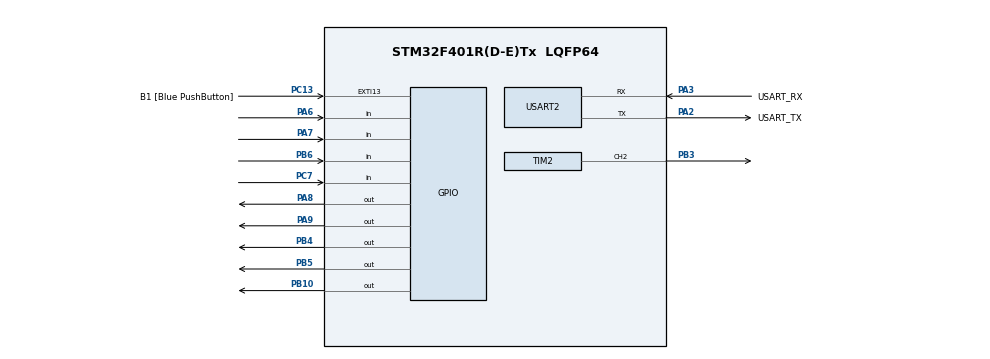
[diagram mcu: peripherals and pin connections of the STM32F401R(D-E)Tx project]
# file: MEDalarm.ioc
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Mcu.Family=STM32F4
Mcu.Name=STM32F401R(D-E)Tx
Mcu.Package=LQFP64
NVIC.PriorityGroup=NVIC_PRIORITYGROUP_0
PA13.GPIO_Label=TMS
PA13.Mode=Serial_Wire
PA13.Signal=SYS_JTMS-SWDIO
PA14.GPIO_Label=TCK
PA14.Mode=Serial_Wire
PA14.Signal=SYS_JTCK-SWCLK
PA2.GPIO_Label=USART_TX
PA2.GPIO_Mode=GPIO_MODE_AF_PP
PA2.GPIO_PuPd=GPIO_NOPULL
PA2.GPIO_Speed=GPIO_SPEED_FREQ_LOW
PA2.Mode=Asynchronous
PA2.Signal=USART2_TX
PA3.GPIO_Label=USART_RX
PA3.GPIO_Mode=GPIO_MODE_AF_PP
PA3.GPIO_PuPd=GPIO_NOPULL
PA3.GPIO_Speed=GPIO_SPEED_FREQ_LOW
PA3.Mode=Asynchronous
PA3.Signal=USART2_RX
PA6.Signal=GPIO_Input
PA7.Signal=GPIO_Input
PA8.Signal=GPIO_Output
PA9.Signal=GPIO_Output
PB10.Signal=GPIO_Output
PB3.Signal=S_TIM2_CH2
PB4.Signal=GPIO_Output
PB5.Signal=GPIO_Output
PB6.Signal=GPIO_Input
PC13-ANTI_TAMP.GPIO_Label=B1 [Blue PushButton]
PC13-ANTI_TAMP.GPIO_ModeDefaultEXTI=GPIO_MODE_IT_FALLING
PC13-ANTI_TAMP.GPIO_PuPd=GPIO_NOPULL
PC13-ANTI_TAMP.Signal=GPXTI13
PC14-OSC32_IN.Mode=LSE-External-Oscillator
PC14-OSC32_IN.Signal=RCC_OSC32_IN
PC15-OSC32_OUT.Mode=LSE-External-Oscillator
PC15-OSC32_OUT.Signal=RCC_OSC32_OUT
PC7.Signal=GPIO_Input
PH0\ -\ OSC_IN.Mode=HSE-External-Clock-Source
PH0\ -\ OSC_IN.Signal=RCC_OSC_IN
PH1\ -\ OSC_OUT.Mode=HSE-External-Clock-Source
PH1\ -\ OSC_OUT.Signal=RCC_OSC_OUT
ProjectManager.HeapSize=0x200
ProjectManager.StackSize=0x400
ProjectManager.TargetToolchain=STM32CubeIDE
RCC.48MHZClocksFreq_Value=48000000
RCC.AHBFreq_Value=84000000
RCC.APB1CLKDivider=RCC_HCLK_DIV2
RCC.APB1Freq_Value=42000000
RCC.APB1TimFreq_Value=84000000
RCC.APB2Freq_Value=84000000
RCC.APB2TimFreq_Value=84000000
RCC.CortexFreq_Value=84000000
RCC.HCLKFreq_Value=84000000
RCC.HSE_VALUE=8000000
RCC.HSI_VALUE=16000000
RCC.PLLN=336
RCC.PLLP=RCC_PLLP_DIV4
RCC.PLLQ=7
RCC.SYSCLKFreq_VALUE=84000000
RCC.SYSCLKSource=RCC_SYSCLKSOURCE_PLLCLK
RCC.VCOOutputFreq_Value=336000000
SH.S_TIM2_CH2.0=TIM2_CH2,PWM Generation2 CH2
TIM2.Channel-PWM\ Generation2\ CH2=TIM_CHANNEL_2
TIM2.Period=9999
TIM2.Prescaler=15
TIM2.Pulse-PWM\ Generation2\ CH2=1
USART2.VirtualMode=VM_ASYNC
VP_TIM2_VS_ClockSourceINT.Mode=Internal
board=NUCLEO-F401RE

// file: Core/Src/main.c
/* USER CODE BEGIN Header */
/**
  ******************************************************************************
  * @file           : main.c
  * @brief          : Main program body
  ******************************************************************************
  * @attention
  *
  * Copyright (c) 2023 STMicroelectronics.
  * All rights reserved.
  *
  * This software is licensed under terms that can be found in the LICENSE file
  * in the root directory of this software component.
  * If no LICENSE file comes with this software, it is provided AS-IS.
  *
  ******************************************************************************
  */
/* USER CODE END Header */
#include "main.h"

/* USER CODE BEGIN Includes */
#include "lcd.h"
/* USER CODE END Includes */

TIM_HandleTypeDef htim2;

UART_HandleTypeDef huart2;

/* USER CODE BEGIN PV */
int countdown = 60000;
int originalTime = 60000;
int	servoState = 0;
int buttonState = 0;
int lastButtonState = 1;
int complete = 0;
int firstTime = 1;
/* USER CODE END PV */

void SystemClock_Config(void);
static void MX_GPIO_Init(void);
static void MX_USART2_UART_Init(void);
static void MX_TIM2_Init(void);
/* USER CODE BEGIN PFP */
void showTimer(void);
void openBox(void);
void setTimer(void);
/* USER CODE END PFP */

int main(void)
{

  /* MCU Configuration--------------------------------------------------------*/

  /* Reset of all peripherals, Initializes the Flash interface and the Systick. */
  HAL_Init();

  /* Configure the system clock */
  SystemClock_Config();

  /* Initialize all configured peripherals */
  MX_GPIO_Init();
  MX_USART2_UART_Init();
  MX_TIM2_Init();
  /* USER CODE BEGIN 2 */

  HAL_TIM_PWM_Start(&htim2, TIM_CHANNEL_2);
  /* USER CODE END 2 */

  /* Infinite loop */
  /* USER CODE BEGIN WHILE */
  while (1)
  {
	  openBox();

//	  //If the user is in set timer mode
	  if(HAL_GPIO_ReadPin(GPIOA, GPIO_PIN_6) == GPIO_PIN_SET){

		  		__HAL_TIM_SET_COMPARE(&htim2,TIM_CHANNEL_2, 3600);

		  		// Lcd_PortType ports[] = { D4_GPIO_Port, D5_GPIO_Port, D6_GPIO_Port, D7_GPIO_Port };
		  		Lcd_PortType ports[] = { GPIOB, GPIOB, GPIOA, GPIOA };
		  		// Lcd_PinType pins[] = {D4_Pin, D5_Pin, D6_Pin, D7_Pin};
		  		Lcd_PinType pins[] = {GPIO_PIN_4, GPIO_PIN_5, GPIO_PIN_5, GPIO_PIN_10};
		  		Lcd_HandleTypeDef lcd;
		  		// Lcd_create(ports, pins, RS_GPIO_Port, RS_Pin, EN_GPIO_Port, EN_Pin, LCD_4_BIT_MODE);
		  		lcd = Lcd_create(ports, pins, GPIOA, GPIO_PIN_9, GPIOA, GPIO_PIN_8, LCD_4_BIT_MODE);
		  		Lcd_cursor(&lcd, 0,1);
		  		Lcd_string(&lcd, "Set Time(H:M)");

		  		Lcd_cursor(&lcd, 1,1);
		  		Lcd_int(&lcd, (countdown/3600000));
		  		Lcd_string(&lcd, ":");
		  		Lcd_int(&lcd, ((countdown/60000)%60));
		  		HAL_Delay(500);

		  		setTimer();

		  		if(countdown != 0){
		  			originalTime = countdown;
		  		}
	  }
	  //If the countdown is going and user not in set time mode
	  else if(countdown > 0){
		  complete = 0;
		  firstTime = 1;
		  //Close servo during timer countdown
		  __HAL_TIM_SET_COMPARE(&htim2,TIM_CHANNEL_2, 1000);

		  showTimer();
		  countdown -= 1000;
		  HAL_Delay(1000);
	  }

	  //If the timer reaches zero and the user is not setting the time
	  else if(countdown == 0){
		  //Display message saying to take medicine

		  // Lcd_PortType ports[] = { D4_GPIO_Port, D5_GPIO_Port, D6_GPIO_Port, D7_GPIO_Port };
		  Lcd_PortType ports[] = { GPIOB, GPIOB, GPIOA, GPIOA };
		  // Lcd_PinType pins[] = {D4_Pin, D5_Pin, D6_Pin, D7_Pin};
		  Lcd_PinType pins[] = {GPIO_PIN_4, GPIO_PIN_5, GPIO_PIN_5, GPIO_PIN_10};
		  Lcd_HandleTypeDef lcd;
		  // Lcd_create(ports, pins, RS_GPIO_Port, RS_Pin, EN_GPIO_Port, EN_Pin, LCD_4_BIT_MODE);
		  lcd = Lcd_create(ports, pins, GPIOA, GPIO_PIN_9, GPIOA, GPIO_PIN_8, LCD_4_BIT_MODE);
		  Lcd_cursor(&lcd, 0,1);
		  Lcd_string(&lcd, "Take Meds!");

		  //Turn on buzzer, then turn off when button is pressed
		  HAL_GPIO_WritePin(GPIOB, GPIO_PIN_10, GPIO_PIN_SET);

		  //Open box if button is pressed
		  openBox();

		  if(complete == 1){
			  HAL_GPIO_WritePin(GPIOB, GPIO_PIN_10, GPIO_PIN_RESET);
		  }
	  }

    /* USER CODE END WHILE */

  }
}

void SystemClock_Config(void)
{
  RCC_OscInitTypeDef RCC_OscInitStruct = {0};
  RCC_ClkInitTypeDef RCC_ClkInitStruct = {0};

  /** Configure the main internal regulator output voltage
  */
  __HAL_RCC_PWR_CLK_ENABLE();
  __HAL_PWR_VOLTAGESCALING_CONFIG(PWR_REGULATOR_VOLTAGE_SCALE2);

  /** Initializes the RCC Oscillators according to the specified parameters
  * in the RCC_OscInitTypeDef structure.
  */
  RCC_OscInitStruct.OscillatorType = RCC_OSCILLATORTYPE_HSI;
  RCC_OscInitStruct.HSIState = RCC_HSI_ON;
  RCC_OscInitStruct.HSICalibrationValue = RCC_HSICALIBRATION_DEFAULT;
  RCC_OscInitStruct.PLL.PLLState = RCC_PLL_ON;
  RCC_OscInitStruct.PLL.PLLSource = RCC_PLLSOURCE_HSI;
  RCC_OscInitStruct.PLL.PLLM = 8;
  RCC_OscInitStruct.PLL.PLLN = 90;
  RCC_OscInitStruct.PLL.PLLP = RCC_PLLP_DIV4;
  RCC_OscInitStruct.PLL.PLLQ = 7;
  if (HAL_RCC_OscConfig(&RCC_OscInitStruct) != HAL_OK)
  {
    Error_Handler();
  }

  /** Initializes the CPU, AHB and APB buses clocks
  */
  RCC_ClkInitStruct.ClockType = RCC_CLOCKTYPE_HCLK|RCC_CLOCKTYPE_SYSCLK
                              |RCC_CLOCKTYPE_PCLK1|RCC_CLOCKTYPE_PCLK2;
  RCC_ClkInitStruct.SYSCLKSource = RCC_SYSCLKSOURCE_PLLCLK;
  RCC_ClkInitStruct.AHBCLKDivider = RCC_SYSCLK_DIV1;
  RCC_ClkInitStruct.APB1CLKDivider = RCC_HCLK_DIV2;
  RCC_ClkInitStruct.APB2CLKDivider = RCC_HCLK_DIV1;

  if (HAL_RCC_ClockConfig(&RCC_ClkInitStruct, FLASH_LATENCY_1) != HAL_OK)
  {
    Error_Handler();
  }
}

static void MX_TIM2_Init(void)
{

  TIM_ClockConfigTypeDef sClockSourceConfig = {0};
  TIM_MasterConfigTypeDef sMasterConfig = {0};
  TIM_OC_InitTypeDef sConfigOC = {0};

  htim2.Instance = TIM2;
  htim2.Init.Prescaler = 15;
  htim2.Init.CounterMode = TIM_COUNTERMODE_UP;
  htim2.Init.Period = 9999;
  htim2.Init.ClockDivision = TIM_CLOCKDIVISION_DIV1;
  htim2.Init.AutoReloadPreload = TIM_AUTORELOAD_PRELOAD_DISABLE;
  if (HAL_TIM_Base_Init(&htim2) != HAL_OK)
  {
    Error_Handler();
  }
  sClockSourceConfig.ClockSource = TIM_CLOCKSOURCE_INTERNAL;
  if (HAL_TIM_ConfigClockSource(&htim2, &sClockSourceConfig) != HAL_OK)
  {
    Error_Handler();
  }
  if (HAL_TIM_PWM_Init(&htim2) != HAL_OK)
  {
    Error_Handler();
  }
  sMasterConfig.MasterOutputTrigger = TIM_TRGO_RESET;
  sMasterConfig.MasterSlaveMode = TIM_MASTERSLAVEMODE_DISABLE;
  if (HAL_TIMEx_MasterConfigSynchronization(&htim2, &sMasterConfig) != HAL_OK)
  {
    Error_Handler();
  }
  sConfigOC.OCMode = TIM_OCMODE_PWM1;
  sConfigOC.Pulse = 1;
  sConfigOC.OCPolarity = TIM_OCPOLARITY_HIGH;
  sConfigOC.OCFastMode = TIM_OCFAST_DISABLE;
  if (HAL_TIM_PWM_ConfigChannel(&htim2, &sConfigOC, TIM_CHANNEL_2) != HAL_OK)
  {
    Error_Handler();
  }
  HAL_TIM_MspPostInit(&htim2);

}

static void MX_USART2_UART_Init(void)
{

  huart2.Instance = USART2;
  huart2.Init.BaudRate = 115200;
  huart2.Init.WordLength = UART_WORDLENGTH_8B;
  huart2.Init.StopBits = UART_STOPBITS_1;
  huart2.Init.Parity = UART_PARITY_NONE;
  huart2.Init.Mode = UART_MODE_TX_RX;
  huart2.Init.HwFlowCtl = UART_HWCONTROL_NONE;
  huart2.Init.OverSampling = UART_OVERSAMPLING_16;
  if (HAL_UART_Init(&huart2) != HAL_OK)
  {
    Error_Handler();
  }

}

static void MX_GPIO_Init(void)
{
  GPIO_InitTypeDef GPIO_InitStruct = {0};

  /* GPIO Ports Clock Enable */
  __HAL_RCC_GPIOC_CLK_ENABLE();
  __HAL_RCC_GPIOH_CLK_ENABLE();
  __HAL_RCC_GPIOA_CLK_ENABLE();
  __HAL_RCC_GPIOB_CLK_ENABLE();

  /*Configure GPIO pin Output Level */
  HAL_GPIO_WritePin(GPIOA, GPIO_PIN_5|GPIO_PIN_8|GPIO_PIN_9|GPIO_PIN_10, GPIO_PIN_RESET);

  /*Configure GPIO pin Output Level */
  HAL_GPIO_WritePin(GPIOB, GPIO_PIN_10|GPIO_PIN_4|GPIO_PIN_5, GPIO_PIN_RESET);

  /*Configure GPIO pin : B1_Pin */
  GPIO_InitStruct.Pin = B1_Pin;
  GPIO_InitStruct.Mode = GPIO_MODE_IT_FALLING;
  GPIO_InitStruct.Pull = GPIO_NOPULL;
  HAL_GPIO_Init(B1_GPIO_Port, &GPIO_InitStruct);

  /*Configure GPIO pins : PA5 PA8 PA9 PA10 */
  GPIO_InitStruct.Pin = GPIO_PIN_5|GPIO_PIN_8|GPIO_PIN_9|GPIO_PIN_10;
  GPIO_InitStruct.Mode = GPIO_MODE_OUTPUT_PP;
  GPIO_InitStruct.Pull = GPIO_NOPULL;
  GPIO_InitStruct.Speed = GPIO_SPEED_FREQ_LOW;
  HAL_GPIO_Init(GPIOA, &GPIO_InitStruct);

  /*Configure GPIO pins : PA6 PA7 */
  GPIO_InitStruct.Pin = GPIO_PIN_6|GPIO_PIN_7;
  GPIO_InitStruct.Mode = GPIO_MODE_INPUT;
  GPIO_InitStruct.Pull = GPIO_NOPULL;
  HAL_GPIO_Init(GPIOA, &GPIO_InitStruct);

  /*Configure GPIO pins : PB10 PB4 PB5 */
  GPIO_InitStruct.Pin = GPIO_PIN_10|GPIO_PIN_4|GPIO_PIN_5;
  GPIO_InitStruct.Mode = GPIO_MODE_OUTPUT_PP;
  GPIO_InitStruct.Pull = GPIO_NOPULL;
  GPIO_InitStruct.Speed = GPIO_SPEED_FREQ_LOW;
  HAL_GPIO_Init(GPIOB, &GPIO_InitStruct);

  /*Configure GPIO pin : PC7 */
  GPIO_InitStruct.Pin = GPIO_PIN_7;
  GPIO_InitStruct.Mode = GPIO_MODE_INPUT;
  GPIO_InitStruct.Pull = GPIO_NOPULL;
  HAL_GPIO_Init(GPIOC, &GPIO_InitStruct);

  /*Configure GPIO pin : PB6 */
  GPIO_InitStruct.Pin = GPIO_PIN_6;
  GPIO_InitStruct.Mode = GPIO_MODE_INPUT;
  GPIO_InitStruct.Pull = GPIO_NOPULL;
  HAL_GPIO_Init(GPIOB, &GPIO_InitStruct);

}

/* USER CODE BEGIN 4 */

void showTimer(void){
	// Lcd_PortType ports[] = { D4_GPIO_Port, D5_GPIO_Port, D6_GPIO_Port, D7_GPIO_Port };
		Lcd_PortType ports[] = { GPIOB, GPIOB, GPIOA, GPIOA};
		// Lcd_PinType pins[] = {D4_Pin, D5_Pin, D6_Pin, D7_Pin};
		Lcd_PinType pins[] = {GPIO_PIN_4, GPIO_PIN_5, GPIO_PIN_5, GPIO_PIN_10};
		Lcd_HandleTypeDef lcd;
		// Lcd_create(ports, pins, RS_GPIO_Port, RS_Pin, EN_GPIO_Port, EN_Pin, LCD_4_BIT_MODE);
		lcd = Lcd_create(ports, pins, GPIOA, GPIO_PIN_9, GPIOA, GPIO_PIN_8, LCD_4_BIT_MODE);
		Lcd_cursor(&lcd, 0,1);
		Lcd_string(&lcd, "Time Left");

		Lcd_cursor(&lcd, 1,1);
		//Hours:Min:Sec
		Lcd_int(&lcd, (countdown/3600000));
		Lcd_string(&lcd, ":");
		Lcd_int(&lcd, ((countdown/60000)%60));
		Lcd_string(&lcd, ":");
		Lcd_int(&lcd, ((countdown/1000)%60));
}

void setTimer(void){

		if (firstTime == 1){
			countdown = 0;
		}

		if(HAL_GPIO_ReadPin(GPIOA, GPIO_PIN_7) == GPIO_PIN_SET){
			countdown += 3600000;
		}
		else if(HAL_GPIO_ReadPin(GPIOB, GPIO_PIN_6) == GPIO_PIN_SET){
			countdown += 60000;
		}

		firstTime = 0;
}

void openBox(void){
	//Determine if button is pressed
	buttonState = HAL_GPIO_ReadPin(GPIOC, GPIO_PIN_7);

	// Check if the button state has changed (button press detected)
	if (buttonState != lastButtonState) {
	    // If the button is pressed (LOW), and the servo is at 0 degrees, rotate it to 90 degrees
	    if (buttonState == GPIO_PIN_SET && servoState == 0) {
	    	//turn off buzzer
    		HAL_GPIO_WritePin(GPIOB, GPIO_PIN_10, GPIO_PIN_RESET);
	    	__HAL_TIM_SET_COMPARE(&htim2,TIM_CHANNEL_2, 3600);
	    	complete = 1;
	    	servoState = 90; // Update the servo state
	    }
	    // If the button is pressed (LOW), and the servo is at 90 degrees, rotate it back to 0 degrees
	    else if (buttonState == GPIO_PIN_SET && servoState == 90) {
	    	//turn off buzzer
    		HAL_GPIO_WritePin(GPIOB, GPIO_PIN_10, GPIO_PIN_RESET);
	    	__HAL_TIM_SET_COMPARE(&htim2,TIM_CHANNEL_2, 1000);
	    	servoState = 0; // Update the servo state
	    	countdown = originalTime;
	    }
	  }

	lastButtonState = buttonState;
}

/* USER CODE END 4 */

void Error_Handler(void)
{
  __disable_irq();
  while (1)
  {
  }
}
